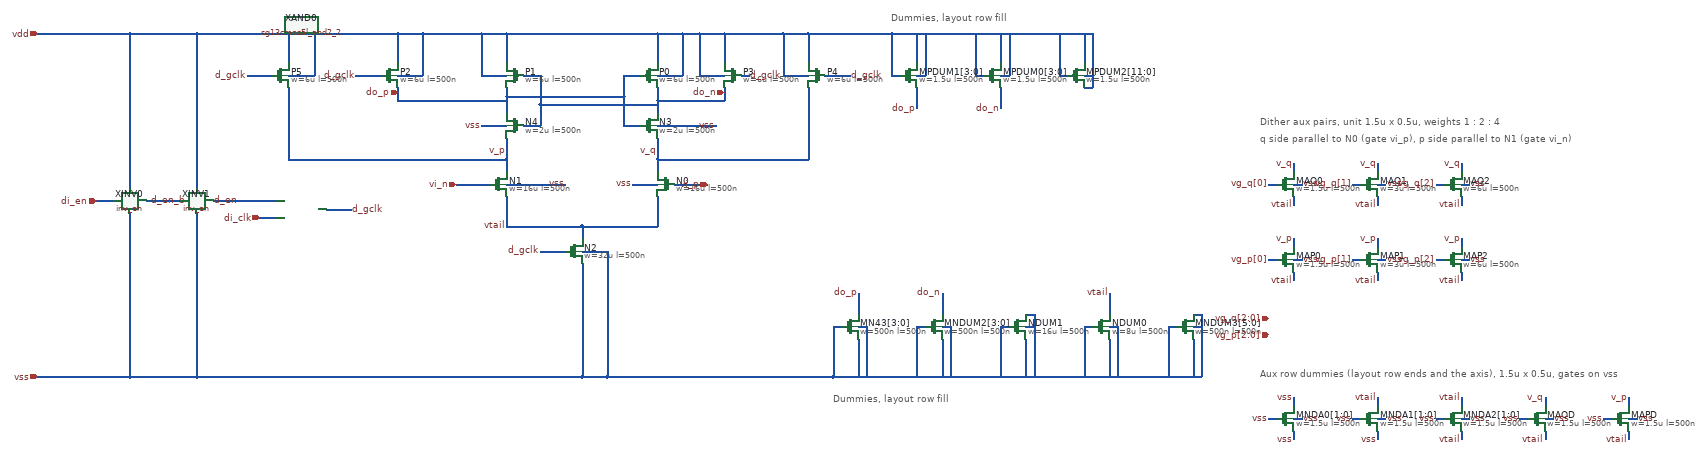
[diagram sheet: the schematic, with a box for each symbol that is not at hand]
v {xschem version=3.4.8RC file_version=1.3}
G {}
K {}
V {}
S {}
F {}
E {}
N 480 -1900 700 -1900 {lab=vdd}
N 480 -1080 700 -1080 {lab=vss}
N 620 -1500 660 -1500 {lab=di_en}
N 700 -1900 700 -1530 {lab=vdd}
N 700 -1470 700 -1080 {lab=vss}
N 740 -1500 820 -1500 {lab=d_en_b}
N 860 -1900 860 -1530 {lab=vdd}
N 860 -1470 860 -1080 {lab=vss}
N 1010 -1460 1050 -1460 {lab=di_clk}
N 1170 -1480 1230 -1480 {lab=d_gclk}
N 1080 -1900 1080 -1830 {lab=vdd}
N 1080 -1800 1140 -1800 {lab=vdd}
N 1140 -1900 1140 -1800 {lab=vdd}
N 980 -1800 1040 -1800 {lab=d_gclk}
N 1080 -1770 1080 -1600 {lab=v_p}
N 1080 -1600 1600 -1600 {lab=v_p}
N 1340 -1900 1340 -1830 {lab=vdd}
N 1340 -1800 1400 -1800 {lab=vdd}
N 1400 -1900 1400 -1800 {lab=vdd}
N 1240 -1800 1300 -1800 {lab=d_gclk}
N 1340 -1770 1340 -1740 {lab=do_p}
N 1340 -1740 1600 -1740 {lab=do_p}
N 2120 -1900 2120 -1830 {lab=vdd}
N 2060 -1800 2120 -1800 {lab=vdd}
N 2060 -1900 2060 -1800 {lab=vdd}
N 2160 -1800 2180 -1800 {lab=d_gclk}
N 2120 -1770 2120 -1740 {lab=do_n}
N 1960 -1740 2120 -1740 {lab=do_n}
N 2320 -1900 2320 -1830 {lab=vdd}
N 2260 -1800 2320 -1800 {lab=vdd}
N 2260 -1900 2260 -1800 {lab=vdd}
N 2360 -1800 2420 -1800 {lab=d_gclk}
N 2320 -1770 2320 -1600 {lab=v_q}
N 1960 -1600 2320 -1600 {lab=v_q}
N 1600 -1900 1600 -1830 {lab=vdd}
N 1540 -1800 1600 -1800 {lab=vdd}
N 1540 -1900 1540 -1800 {lab=vdd}
N 1960 -1900 1960 -1830 {lab=vdd}
N 1960 -1800 2020 -1800 {lab=vdd}
N 2020 -1900 2020 -1800 {lab=vdd}
N 1540 -1680 1600 -1680 {lab=vss}
N 1960 -1680 2100 -1680 {lab=vss}
N 1600 -1540 1740 -1540 {lab=vss}
N 1900 -1540 1960 -1540 {lab=vss}
N 1600 -1740 1600 -1710 {lab=do_p}
N 1960 -1730 1960 -1710 {lab=do_n}
N 1600 -1600 1600 -1570 {lab=v_p}
N 1960 -1600 1960 -1570 {lab=v_q}
N 1600 -1510 1600 -1440 {lab=vtail}
N 1600 -1440 1780 -1440 {lab=vtail}
N 1780 -1440 1960 -1440 {lab=vtail}
N 1960 -1510 1960 -1440 {lab=vtail}
N 1780 -1440 1780 -1410 {lab=vtail}
N 1780 -1350 1780 -1080 {lab=vss}
N 1680 -1380 1740 -1380 {lab=d_gclk}
N 1780 -1380 1840 -1380 {lab=vss}
N 1840 -1380 1840 -1080 {lab=vss}
N 1640 -1800 1680 -1800 {lab=do_n}
N 1680 -1800 1680 -1730 {lab=do_n}
N 1680 -1730 1680 -1680 {lab=do_n}
N 1640 -1680 1680 -1680 {lab=do_n}
N 1680 -1730 1960 -1730 {lab=do_n}
N 1880 -1800 1920 -1800 {lab=do_p}
N 1880 -1800 1880 -1750 {lab=do_p}
N 1880 -1750 1880 -1680 {lab=do_p}
N 1880 -1680 1920 -1680 {lab=do_p}
N 1600 -1750 1880 -1750 {lab=do_p}
N 1480 -1540 1560 -1540 {lab=vi_n}
N 2000 -1540 2080 -1540 {lab=vi_p}
N 2440 -1170 2440 -1080 {lab=vss}
N 2440 -1200 2460 -1200 {lab=vss}
N 2460 -1200 2460 -1080 {lab=vss}
N 2380 -1200 2400 -1200 {lab=vss}
N 2380 -1200 2380 -1080 {lab=vss}
N 2440 -1280 2440 -1230 {lab=do_p}
N 2640 -1170 2640 -1080 {lab=vss}
N 2640 -1200 2660 -1200 {lab=vss}
N 2660 -1200 2660 -1080 {lab=vss}
N 2580 -1200 2600 -1200 {lab=vss}
N 2580 -1200 2580 -1080 {lab=vss}
N 2640 -1280 2640 -1230 {lab=do_n}
N 2840 -1170 2840 -1080 {lab=vss}
N 2840 -1200 2860 -1200 {lab=vss}
N 2860 -1200 2860 -1080 {lab=vss}
N 2780 -1200 2800 -1200 {lab=vss}
N 2780 -1200 2780 -1080 {lab=vss}
N 2860 -1230 2860 -1200 {lab=vss}
N 3040 -1170 3040 -1080 {lab=vss}
N 3040 -1200 3060 -1200 {lab=vss}
N 3060 -1200 3060 -1080 {lab=vss}
N 2980 -1200 3000 -1200 {lab=vss}
N 2980 -1200 2980 -1080 {lab=vss}
N 3040 -1280 3040 -1230 {lab=vtail}
N 2580 -1900 2580 -1830 {lab=vdd}
N 2580 -1800 2600 -1800 {lab=vdd}
N 2600 -1900 2600 -1800 {lab=vdd}
N 2520 -1800 2540 -1800 {lab=vdd}
N 2520 -1900 2520 -1800 {lab=vdd}
N 2580 -1770 2580 -1720 {lab=do_p}
N 2780 -1900 2780 -1830 {lab=vdd}
N 2780 -1800 2800 -1800 {lab=vdd}
N 2800 -1900 2800 -1800 {lab=vdd}
N 2720 -1800 2740 -1800 {lab=vdd}
N 2720 -1900 2720 -1800 {lab=vdd}
N 2780 -1770 2780 -1720 {lab=do_n}
N 2980 -1900 2980 -1830 {lab=vdd}
N 2980 -1770 3000 -1770 {lab=vdd}
N 3000 -1800 3000 -1770 {lab=vdd}
N 2920 -1800 2940 -1800 {lab=vdd}
N 2920 -1900 2920 -1800 {lab=vdd}
N 700 -1900 860 -1900 {lab=vdd}
N 700 -1080 860 -1080 {lab=vss}
N 860 -1900 1140 -1900 {lab=vdd}
N 1140 -1900 1200 -1900 {lab=vdd}
N 1600 -1650 1600 -1600 {lab=v_p}
N 1200 -1900 1340 -1900 {lab=vdd}
N 1340 -1900 1400 -1900 {lab=vdd}
N 1600 -1750 1600 -1740 {lab=do_p}
N 2060 -1900 2120 -1900 {lab=vdd}
N 2020 -1900 2060 -1900 {lab=vdd}
N 1960 -1770 1960 -1740 {lab=do_n}
N 2260 -1900 2320 -1900 {lab=vdd}
N 2120 -1900 2260 -1900 {lab=vdd}
N 1960 -1650 1960 -1600 {lab=v_q}
N 1540 -1900 1600 -1900 {lab=vdd}
N 1400 -1900 1540 -1900 {lab=vdd}
N 1600 -1900 1960 -1900 {lab=vdd}
N 1960 -1900 2020 -1900 {lab=vdd}
N 1780 -1080 1840 -1080 {lab=vss}
N 1960 -1740 1960 -1730 {lab=do_n}
N 1600 -1770 1600 -1750 {lab=do_p}
N 1840 -1080 2380 -1080 {lab=vss}
N 2320 -1900 2520 -1900 {lab=vdd}
N 900 -1500 1050 -1500 {lab=d_en}
N 860 -1080 1780 -1080 {lab=vss}
N 2840 -1230 2860 -1230 {lab=vss}
N 2980 -1800 3000 -1800 {lab=vdd}
N 3000 -1900 3000 -1800 {lab=vdd}
N 3240 -1170 3240 -1080 {lab=vss}
N 3240 -1200 3260 -1200 {lab=vss}
N 3260 -1200 3260 -1080 {lab=vss}
N 3180 -1200 3200 -1200 {lab=vss}
N 3180 -1200 3180 -1080 {lab=vss}
N 3240 -1230 3260 -1230 {lab=vss}
N 3260 -1230 3260 -1200 {lab=vss}
N 2380 -1080 3260 -1080 {lab=vss}
N 2520 -1900 3000 -1900 {lab=vdd}
C {iopin.sym} 480 -1900 2 0 {name=l1 lab=vdd}
C {iopin.sym} 480 -1080 2 0 {name=l2 lab=vss}
C {iopin.sym} 620 -1500 2 0 {name=l3 lab=di_en}
C {inv_en.sym} 700 -1500 0 0 {name=XINV0
}
C {lab_wire.sym} 750 -1500 0 1 {name=l4 lab=d_en_b}
C {inv_en.sym} 860 -1500 0 0 {name=XINV1
}
C {lab_wire.sym} 960 -1500 0 0 {name=l5 lab=d_en}
C {iopin.sym} 1010 -1460 2 0 {name=l6 lab=di_clk}
C {sg13cmos5l_stdcells/sg13cmos5l_and2_2.sym} 1110 -1480 0 0 {name=XAND0
VDD=vdd
VSS=vss
prefix=sg13cmos5l_
}
C {lab_pin.sym} 1230 -1480 2 0 {name=l7 lab=d_gclk}
C {sg13_lv_pmos.sym} 1620 -1800 0 1 {name=P1
l=500n
w=6u
ng=4
m=1
model=sg13_lv_pmos
spiceprefix=X
}
C {sg13_lv_pmos.sym} 1940 -1800 0 0 {name=P0
l=500n
w=6u
ng=4
m=1
model=sg13_lv_pmos
spiceprefix=X
}
C {sg13_lv_nmos.sym} 1620 -1680 0 1 {name=N4
l=500n
w=2u
ng=4
m=1
model=sg13_lv_nmos
spiceprefix=X
}
C {sg13_lv_nmos.sym} 1940 -1680 0 0 {name=N3
l=500n
w=2u
ng=4
m=1
model=sg13_lv_nmos
spiceprefix=X
}
C {sg13_lv_nmos.sym} 1580 -1540 0 0 {name=N1
l=500n
w=16u
ng=4
m=1
model=sg13_lv_nmos
spiceprefix=X
}
C {sg13_lv_nmos.sym} 1980 -1540 0 1 {name=N0
l=500n
w=16u
ng=4
m=1
model=sg13_lv_nmos
spiceprefix=X
}
C {sg13_lv_nmos.sym} 1760 -1380 0 0 {name=N2
l=500n
w=32u
ng=8
m=1
model=sg13_lv_nmos
spiceprefix=X
}
C {sg13_lv_pmos.sym} 1060 -1800 0 0 {name=P5
l=500n
w=6u
ng=4
m=1
model=sg13_lv_pmos
spiceprefix=X
}
C {lab_pin.sym} 980 -1800 0 0 {name=l8 lab=d_gclk}
C {sg13_lv_pmos.sym} 1320 -1800 0 0 {name=P2
l=500n
w=6u
ng=4
m=1
model=sg13_lv_pmos
spiceprefix=X
}
C {lab_pin.sym} 1240 -1800 0 0 {name=l9 lab=d_gclk}
C {sg13_lv_pmos.sym} 2140 -1800 0 1 {name=P3
l=500n
w=6u
ng=4
m=1
model=sg13_lv_pmos
spiceprefix=X
}
C {lab_pin.sym} 2180 -1800 2 0 {name=l10 lab=d_gclk}
C {sg13_lv_pmos.sym} 2340 -1800 0 1 {name=P4
l=500n
w=6u
ng=4
m=1
model=sg13_lv_pmos
spiceprefix=X
}
C {lab_pin.sym} 2420 -1800 2 0 {name=l11 lab=d_gclk}
C {lab_pin.sym} 1540 -1680 0 0 {name=l12 lab=vss}
C {lab_pin.sym} 2100 -1680 0 0 {name=l13 lab=vss}
C {lab_pin.sym} 1740 -1540 0 0 {name=l14 lab=vss}
C {lab_pin.sym} 1900 -1540 0 0 {name=l15 lab=vss}
C {lab_wire.sym} 1600 -1620 0 0 {name=l16 lab=v_p}
C {lab_wire.sym} 1960 -1620 0 0 {name=l17 lab=v_q}
C {lab_wire.sym} 1600 -1440 0 0 {name=l18 lab=vtail}
C {lab_pin.sym} 1680 -1380 0 0 {name=l19 lab=d_gclk}
C {iopin.sym} 1340 -1760 2 0 {name=l20 lab=do_p}
C {iopin.sym} 2120 -1760 0 0 {name=l21 lab=do_n}
C {iopin.sym} 1480 -1540 2 0 {name=l22 lab=vi_n}
C {iopin.sym} 2080 -1540 0 0 {name=l23 lab=vi_p}
C {sg13_lv_nmos.sym} 2420 -1200 0 0 {name=MN43[3:0]
l=500n
w=500n
ng=1
m=1
model=sg13_lv_nmos
spiceprefix=X
}
C {lab_pin.sym} 2440 -1280 0 0 {name=l24 lab=do_p}
C {sg13_lv_nmos.sym} 2620 -1200 0 0 {name=MNDUM2[3:0]
l=500n
w=500n
ng=1
m=1
model=sg13_lv_nmos
spiceprefix=X
}
C {lab_pin.sym} 2640 -1280 0 0 {name=l25 lab=do_n}
C {sg13_lv_nmos.sym} 2820 -1200 0 0 {name=NDUM1
l=500n
w=16u
ng=4
m=1
model=sg13_lv_nmos
spiceprefix=X
}
C {sg13_lv_nmos.sym} 3020 -1200 0 0 {name=NDUM0
l=500n
w=8u
ng=2
m=1
model=sg13_lv_nmos
spiceprefix=X
}
C {lab_pin.sym} 3040 -1280 0 0 {name=l26 lab=vtail}
C {sg13_lv_pmos.sym} 2560 -1800 0 0 {name=MPDUM1[3:0]
l=500n
w=1.5u
ng=1
m=1
model=sg13_lv_pmos
spiceprefix=X
}
C {lab_pin.sym} 2580 -1720 0 0 {name=l27 lab=do_p}
C {sg13_lv_pmos.sym} 2760 -1800 0 0 {name=MPDUM0[3:0]
l=500n
w=1.5u
ng=1
m=1
model=sg13_lv_pmos
spiceprefix=X
}
C {lab_pin.sym} 2780 -1720 0 0 {name=l28 lab=do_n}
C {sg13_lv_pmos.sym} 2960 -1800 0 0 {name=MPDUM2[11:0]
l=500n
w=1.5u
ng=1
m=1
model=sg13_lv_pmos
spiceprefix=X
}
C {sg13_lv_nmos.sym} 3220 -1200 0 0 {name=MNDUM3[5:0]
l=500n
w=500n
ng=1
m=1
model=sg13_lv_nmos
spiceprefix=X
}
T {Dummies, layout row fill} 2380 -1040 0 0 0.25 0.25 {}
T {Dummies, layout row fill} 2520 -1950 0 0 0.25 0.25 {}
T {Dither aux pairs, unit 1.5u x 0.5u, weights 1 : 2 : 4} 3400 -1700 0 0 0.4 0.4 {}
T {q side parallel to N0 (gate vi_p), p side parallel to N1 (gate vi_n)} 3400 -1660 0 0 0.3 0.3 {}
C {sg13_lv_nmos.sym} 3460 -1540 0 0 {name=MAQ0
l=500n
w=1.5u
ng=1
m=1
model=sg13_lv_nmos
spiceprefix=X
}
N 3480 -1570 3480 -1590 {lab=v_q}
C {lab_pin.sym} 3480 -1590 3 0 {name=l101 sig_type=std_logic lab=v_q}
N 3480 -1510 3480 -1490 {lab=vtail}
C {lab_pin.sym} 3480 -1490 1 0 {name=l102 sig_type=std_logic lab=vtail}
N 3440 -1540 3420 -1540 {lab=vg_q[0]}
C {lab_pin.sym} 3420 -1540 0 0 {name=l103 sig_type=std_logic lab=vg_q[0]}
N 3480 -1540 3500 -1540 {lab=vss}
C {lab_pin.sym} 3500 -1540 2 0 {name=l104 sig_type=std_logic lab=vss}
C {sg13_lv_nmos.sym} 3660 -1540 0 0 {name=MAQ1
l=500n
w=3u
ng=2
m=1
model=sg13_lv_nmos
spiceprefix=X
}
N 3680 -1570 3680 -1590 {lab=v_q}
C {lab_pin.sym} 3680 -1590 3 0 {name=l105 sig_type=std_logic lab=v_q}
N 3680 -1510 3680 -1490 {lab=vtail}
C {lab_pin.sym} 3680 -1490 1 0 {name=l106 sig_type=std_logic lab=vtail}
N 3640 -1540 3620 -1540 {lab=vg_q[1]}
C {lab_pin.sym} 3620 -1540 0 0 {name=l107 sig_type=std_logic lab=vg_q[1]}
N 3680 -1540 3700 -1540 {lab=vss}
C {lab_pin.sym} 3700 -1540 2 0 {name=l108 sig_type=std_logic lab=vss}
C {sg13_lv_nmos.sym} 3860 -1540 0 0 {name=MAQ2
l=500n
w=6u
ng=4
m=1
model=sg13_lv_nmos
spiceprefix=X
}
N 3880 -1570 3880 -1590 {lab=v_q}
C {lab_pin.sym} 3880 -1590 3 0 {name=l109 sig_type=std_logic lab=v_q}
N 3880 -1510 3880 -1490 {lab=vtail}
C {lab_pin.sym} 3880 -1490 1 0 {name=l110 sig_type=std_logic lab=vtail}
N 3840 -1540 3820 -1540 {lab=vg_q[2]}
C {lab_pin.sym} 3820 -1540 0 0 {name=l111 sig_type=std_logic lab=vg_q[2]}
N 3880 -1540 3900 -1540 {lab=vss}
C {lab_pin.sym} 3900 -1540 2 0 {name=l112 sig_type=std_logic lab=vss}
C {sg13_lv_nmos.sym} 3460 -1360 0 0 {name=MAP0
l=500n
w=1.5u
ng=1
m=1
model=sg13_lv_nmos
spiceprefix=X
}
N 3480 -1390 3480 -1410 {lab=v_p}
C {lab_pin.sym} 3480 -1410 3 0 {name=l113 sig_type=std_logic lab=v_p}
N 3480 -1330 3480 -1310 {lab=vtail}
C {lab_pin.sym} 3480 -1310 1 0 {name=l114 sig_type=std_logic lab=vtail}
N 3440 -1360 3420 -1360 {lab=vg_p[0]}
C {lab_pin.sym} 3420 -1360 0 0 {name=l115 sig_type=std_logic lab=vg_p[0]}
N 3480 -1360 3500 -1360 {lab=vss}
C {lab_pin.sym} 3500 -1360 2 0 {name=l116 sig_type=std_logic lab=vss}
C {sg13_lv_nmos.sym} 3660 -1360 0 0 {name=MAP1
l=500n
w=3u
ng=2
m=1
model=sg13_lv_nmos
spiceprefix=X
}
N 3680 -1390 3680 -1410 {lab=v_p}
C {lab_pin.sym} 3680 -1410 3 0 {name=l117 sig_type=std_logic lab=v_p}
N 3680 -1330 3680 -1310 {lab=vtail}
C {lab_pin.sym} 3680 -1310 1 0 {name=l118 sig_type=std_logic lab=vtail}
N 3640 -1360 3620 -1360 {lab=vg_p[1]}
C {lab_pin.sym} 3620 -1360 0 0 {name=l119 sig_type=std_logic lab=vg_p[1]}
N 3680 -1360 3700 -1360 {lab=vss}
C {lab_pin.sym} 3700 -1360 2 0 {name=l120 sig_type=std_logic lab=vss}
C {sg13_lv_nmos.sym} 3860 -1360 0 0 {name=MAP2
l=500n
w=6u
ng=4
m=1
model=sg13_lv_nmos
spiceprefix=X
}
N 3880 -1390 3880 -1410 {lab=v_p}
C {lab_pin.sym} 3880 -1410 3 0 {name=l121 sig_type=std_logic lab=v_p}
N 3880 -1330 3880 -1310 {lab=vtail}
C {lab_pin.sym} 3880 -1310 1 0 {name=l122 sig_type=std_logic lab=vtail}
N 3840 -1360 3820 -1360 {lab=vg_p[2]}
C {lab_pin.sym} 3820 -1360 0 0 {name=l123 sig_type=std_logic lab=vg_p[2]}
N 3880 -1360 3900 -1360 {lab=vss}
C {lab_pin.sym} 3900 -1360 2 0 {name=l124 sig_type=std_logic lab=vss}
C {iopin.sym} 3420 -1220 2 0 {name=p125 lab=vg_q[2:0]}
C {iopin.sym} 3420 -1180 2 0 {name=p126 lab=vg_p[2:0]}
T {Aux row dummies (layout row ends and the axis), 1.5u x 0.5u, gates on vss} 3400 -1100 0 0 0.3 0.3 {}
C {sg13_lv_nmos.sym} 3460 -980 0 0 {name=MNDA0[1:0]
l=500n
w=1.5u
ng=1
m=1
model=sg13_lv_nmos
spiceprefix=X
}
N 3480 -1010 3480 -1030 {lab=vss}
C {lab_pin.sym} 3480 -1030 3 0 {name=l401 sig_type=std_logic lab=vss}
N 3480 -950 3480 -930 {lab=vss}
C {lab_pin.sym} 3480 -930 1 0 {name=l402 sig_type=std_logic lab=vss}
N 3440 -980 3420 -980 {lab=vss}
C {lab_pin.sym} 3420 -980 0 0 {name=l403 sig_type=std_logic lab=vss}
N 3480 -980 3500 -980 {lab=vss}
C {lab_pin.sym} 3500 -980 2 0 {name=l404 sig_type=std_logic lab=vss}
C {sg13_lv_nmos.sym} 3660 -980 0 0 {name=MNDA1[1:0]
l=500n
w=1.5u
ng=1
m=1
model=sg13_lv_nmos
spiceprefix=X
}
N 3680 -1010 3680 -1030 {lab=vtail}
C {lab_pin.sym} 3680 -1030 3 0 {name=l405 sig_type=std_logic lab=vtail}
N 3680 -950 3680 -930 {lab=vss}
C {lab_pin.sym} 3680 -930 1 0 {name=l406 sig_type=std_logic lab=vss}
N 3640 -980 3620 -980 {lab=vss}
C {lab_pin.sym} 3620 -980 0 0 {name=l407 sig_type=std_logic lab=vss}
N 3680 -980 3700 -980 {lab=vss}
C {lab_pin.sym} 3700 -980 2 0 {name=l408 sig_type=std_logic lab=vss}
C {sg13_lv_nmos.sym} 3860 -980 0 0 {name=MNDA2[1:0]
l=500n
w=1.5u
ng=1
m=1
model=sg13_lv_nmos
spiceprefix=X
}
N 3880 -1010 3880 -1030 {lab=vtail}
C {lab_pin.sym} 3880 -1030 3 0 {name=l409 sig_type=std_logic lab=vtail}
N 3880 -950 3880 -930 {lab=vtail}
C {lab_pin.sym} 3880 -930 1 0 {name=l410 sig_type=std_logic lab=vtail}
N 3840 -980 3820 -980 {lab=vss}
C {lab_pin.sym} 3820 -980 0 0 {name=l411 sig_type=std_logic lab=vss}
N 3880 -980 3900 -980 {lab=vss}
C {lab_pin.sym} 3900 -980 2 0 {name=l412 sig_type=std_logic lab=vss}
C {sg13_lv_nmos.sym} 4060 -980 0 0 {name=MAQD
l=500n
w=1.5u
ng=1
m=1
model=sg13_lv_nmos
spiceprefix=X
}
N 4080 -1010 4080 -1030 {lab=v_q}
C {lab_pin.sym} 4080 -1030 3 0 {name=l413 sig_type=std_logic lab=v_q}
N 4080 -950 4080 -930 {lab=vtail}
C {lab_pin.sym} 4080 -930 1 0 {name=l414 sig_type=std_logic lab=vtail}
N 4040 -980 4020 -980 {lab=vss}
C {lab_pin.sym} 4020 -980 0 0 {name=l415 sig_type=std_logic lab=vss}
N 4080 -980 4100 -980 {lab=vss}
C {lab_pin.sym} 4100 -980 2 0 {name=l416 sig_type=std_logic lab=vss}
C {sg13_lv_nmos.sym} 4260 -980 0 0 {name=MAPD
l=500n
w=1.5u
ng=1
m=1
model=sg13_lv_nmos
spiceprefix=X
}
N 4280 -1010 4280 -1030 {lab=v_p}
C {lab_pin.sym} 4280 -1030 3 0 {name=l417 sig_type=std_logic lab=v_p}
N 4280 -950 4280 -930 {lab=vtail}
C {lab_pin.sym} 4280 -930 1 0 {name=l418 sig_type=std_logic lab=vtail}
N 4240 -980 4220 -980 {lab=vss}
C {lab_pin.sym} 4220 -980 0 0 {name=l419 sig_type=std_logic lab=vss}
N 4280 -980 4300 -980 {lab=vss}
C {lab_pin.sym} 4300 -980 2 0 {name=l420 sig_type=std_logic lab=vss}
C {title.sym} 480 -1000 0 0 {name=l0 author="(c) 2026 Michael Koefinger"}
